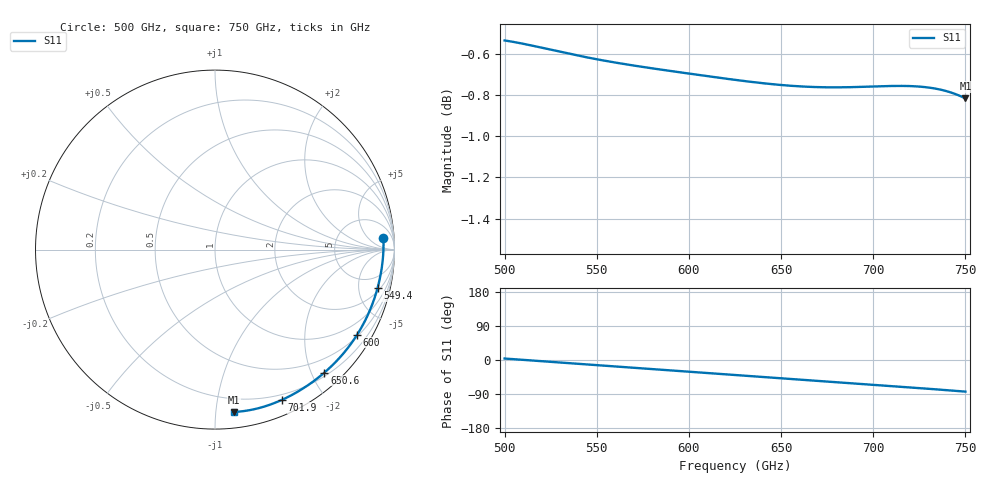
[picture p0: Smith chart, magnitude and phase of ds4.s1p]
!Created with skrf (http://scikit-rf.org).
# GHz S RI R 50.0
!freq ReS11 ImS11
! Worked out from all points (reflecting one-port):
!   401 points, 500 GHz to 750 GHz, reference 50 ohm
!   lowest |S11| = -0.8 dB at 750 GHz (marker M1), VSWR 21.30, Z = 5.28 - j55.8 ohm
!   phase of S11 starts at 4 deg and turns -87 deg over the sweep
!   S11 on the Smith chart (normalised r, x): 500 GHz: 15, +16; 549.4 GHz: 2.44, -7.81; 600 GHz: 0.55, -3.54; 650.6 GHz: 0.26, -2.20; 701.9 GHz: 0.15, -1.53; 750 GHz: 0.11, -1.12
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500  0.9382 0.0641
501.25  0.9384 0.0568
508.125  0.9388 0.0166
515  0.9373 -0.023
523.125  0.9333 -0.0693
531.25  0.9271 -0.1149
540  0.918 -0.1633
549.375  0.9056 -0.2144
562.5  0.8837 -0.2845
570  0.8689 -0.3238
578.125  0.8508 -0.3656
593.75  0.8106 -0.4434
600  0.7925 -0.4734
612.5  0.753 -0.5311
625  0.7094 -0.5855
638.125  0.6599 -0.6387
650.625  0.6094 -0.6854
656.25  0.5857 -0.7052
671.875  0.5172 -0.7561
687.5  0.4445 -0.801
701.875  0.3737 -0.8368
710.625  0.3285 -0.8558
718.75  0.2851 -0.8712
726.875  0.2401 -0.8842
735  0.1935 -0.8944
741.875  0.153 -0.9005
748.75  0.1116 -0.904
750  0.104 -0.9044
